! (c) 2009  Infineon Technologies AG, Munich
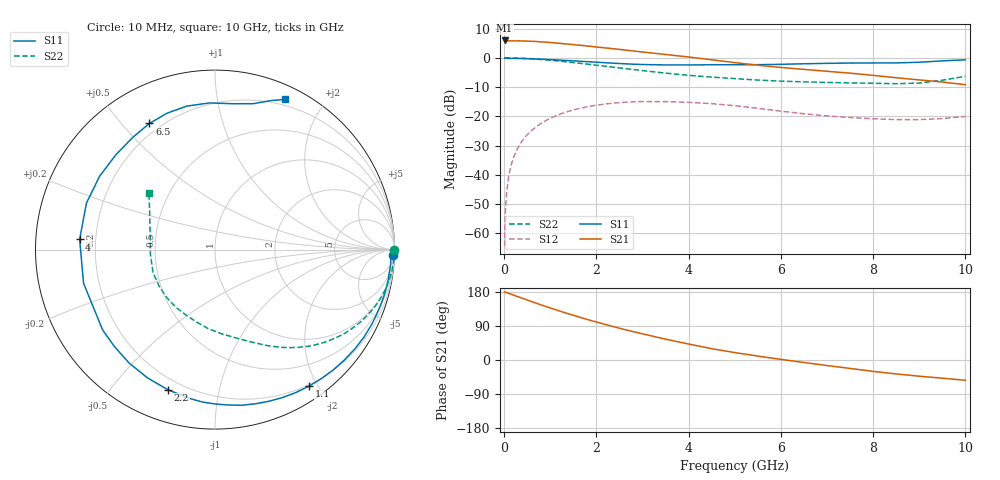
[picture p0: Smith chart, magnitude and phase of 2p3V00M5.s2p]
! Infineon Technologies  Discrete & RF Semiconductors
! BFP420
! VCE =  3.0 V,  IC =  0.5 mA
! Common Emitter S-Parameters:  Nov 2009
# GHz  S  MA  R  50
!  f  S11  S21  S12  S22
! GHz  MAG  ANG  MAG  ANG  MAG  ANG  MAG  ANG
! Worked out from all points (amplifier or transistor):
!   46 points, 10 MHz to 10 GHz, reference 50 ohm
!   highest |S21| = 6.0 dB at 10 MHz (marker M1)
!   |S21| within 3 dB of that: start of sweep to 2.463 GHz
!   unconditionally stable (mu >= 1): 4.452 GHz to end of sweep
!   at 300 MHz: K = 0.02, MSG = 18.3 dB, |S12| = -30.7 dB
!   at 1.7 GHz: K = 0.26, MSG = 10.6 dB, |S12| = -17.1 dB
!   at 10 GHz: K = 1.57, MAG = 1.0 dB, |S12| = -20.1 dB
!   lowest NFmin = 0.68 dB at 900 MHz
!   S11 on the Smith chart (normalised r, x): 10 MHz: 22, -64; 1.1 GHz: 0.18, -1.89; 2.2 GHz: 0.15, -0.71; 4 GHz: 0.14, +0.04; 6.5 GHz: 0.16, +0.60; 10 GHz: 0.14, +1.56
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0.01  0.9904 -1.6  1.984 179.4  0.0006 98.5  0.9991 -0.1
0.02  0.981 -0.9  1.929 179.5  0.0019 90.8  0.9983 -0.5
0.05  0.9802 -2.5  1.941 178.0  0.0047 88.1  0.9987 -1.3
0.1  0.9822 -4.9  1.952 175.8  0.0097 86.9  0.998 -2.7
0.2  0.9794 -10.0  1.955 171.5  0.0194 83.9  0.9948 -5.5
0.35  0.9742 -17.6  1.95 164.9  0.034 79.1  0.9863 -9.5
0.5  0.9679 -25.2  1.933 158.3  0.0483 74.4  0.9734 -13.4
0.8  0.9478 -40.4  1.877 145.5  0.0756 64.8  0.938 -21.0
1.1  0.9236 -55.5  1.8 133.3  0.1003 55.5  0.8943 -28.0
1.4  0.8968 -70.5  1.715 121.6  0.122 46.3  0.8462 -34.6
1.7  0.8691 -85.0  1.627 110.7  0.1402 37.7  0.797 -40.5
2.2  0.8243 -108.4  1.478 93.6  0.1625 24.2  0.7179 -49.3
2.8  0.7785 -136.0  1.309 74.8  0.1767 9.1  0.6309 -58.8
3.5  0.756 -165.6  1.141 55.0  0.1783 -6.2  0.5477 -69.4
4  0.7563 175.7  1.034 42.1  0.1733 -15.3  0.5023 -77.4
4.5  0.7617 160.1  0.927 29.9  0.1644 -23.6  0.4683 -86.2
5.5  0.7641 136.5  0.749 10.3  0.1371 -35.8  0.4167 -104.1
6.5  0.7921 117.5  0.635 -6.6  0.1106 -39.9  0.3884 -123.8
7  0.8056 109.4  0.589 -14.6  0.1015 -39.2  0.3796 -134.5
8.5  0.8186 83.1  0.457 -36.8  0.0878 -31.6  0.3608 -175.5
9  0.8406 75.3  0.419 -42.8  0.0878 -27.3  0.3704 167.3
10  0.9243 64.9  0.347 -53.5  0.0993 -20.8  0.4833 139.4
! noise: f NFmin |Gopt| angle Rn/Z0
0.9  0.68  0.78  35  0.65
1.8  1.42  0.6  75  0.5
2.4  1.57  0.58  98  0.37
3  2.1  0.58  128  0.24
4  2.49  0.57  177  0.09
